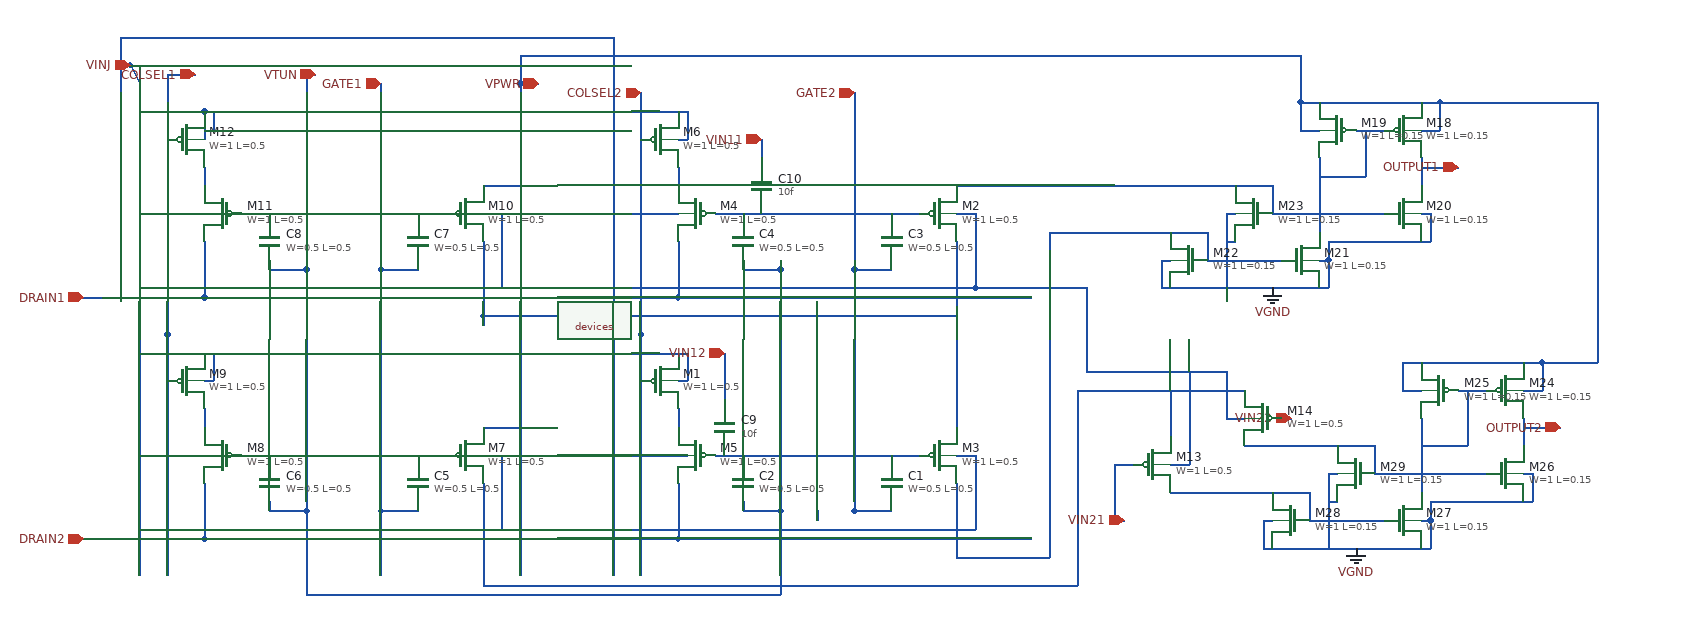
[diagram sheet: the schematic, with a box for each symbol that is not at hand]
v {xschem version=2.9.9 file_version=1.2 }
G {}
K {}
V {}
S {}
E {}
N 1300 -1430 1330 -1430 { lab=#net1}
N 1260 -1380 1260 -1370 { lab=GATE2}
N 1260 -1370 1300 -1370 { lab=GATE2}
N 1140 -1430 1300 -1430 { lab=#net1}
N 1140 -1370 1180 -1370 { lab=VTUN}
N 1140 -1380 1140 -1370 { lab=VTUN}
N 1110 -1430 1140 -1430 { lab=#net1}
N 1070 -1480 1070 -1460 { lab=#net2}
N 1370 -1400 1370 -1320 { lab=#net3}
N 1180 -1380 1180 -1370 { lab=VTUN}
N 1180 -1370 1180 -1300 { lab=VTUN}
N 1180 -1560 1180 -1370 { lab=VTUN}
N 1030 -1560 1030 -1510 { lab=COLSEL2}
N 1030 -1560 1030 -1300 { lab=COLSEL2}
N 1070 -1400 1070 -1340 { lab=DRAIN2}
N 950 -1340 1070 -1340 { lab=DRAIN2}
N 1070 -1340 1220 -1340 { lab=DRAIN2}
N 1220 -1340 1320 -1340 { lab=DRAIN2}
N 1320 -1340 1390 -1340 { lab=DRAIN2}
N 1390 -1340 1450 -1340 { lab=DRAIN2}
N 1000 -1560 1000 -1300 { lab=VINJ}
N 1000 -1540 1070 -1540 { lab=VINJ}
N 1300 -1690 1330 -1690 { lab=#net4}
N 1260 -1640 1260 -1630 { lab=GATE2}
N 1260 -1630 1300 -1630 { lab=GATE2}
N 1140 -1690 1300 -1690 { lab=#net4}
N 1140 -1630 1180 -1630 { lab=VTUN}
N 1140 -1640 1140 -1630 { lab=VTUN}
N 1110 -1690 1140 -1690 { lab=#net4}
N 1070 -1740 1070 -1720 { lab=#net5}
N 1370 -1660 1370 -1580 { lab=#net6}
N 1370 -1720 1410 -1720 { lab=#net7}
N 1260 -1630 1260 -1560 { lab=GATE2}
N 1180 -1640 1180 -1630 { lab=VTUN}
N 1180 -1630 1180 -1560 { lab=VTUN}
N 1030 -1820 1030 -1770 { lab=COLSEL2}
N 1030 -1820 1030 -1560 { lab=COLSEL2}
N 1070 -1660 1070 -1600 { lab=DRAIN1}
N 950 -1600 1070 -1600 { lab=DRAIN1}
N 1070 -1600 1220 -1600 { lab=DRAIN1}
N 1220 -1600 1320 -1600 { lab=DRAIN1}
N 1320 -1600 1390 -1600 { lab=DRAIN1}
N 1390 -1600 1450 -1600 { lab=DRAIN1}
N 1000 -1820 1000 -1560 { lab=VINJ}
N 1000 -1800 1070 -1800 { lab=VINJ}
N 790 -1430 820 -1430 { lab=#net8}
N 750 -1380 750 -1370 { lab=GATE1}
N 750 -1370 790 -1370 { lab=GATE1}
N 630 -1430 790 -1430 { lab=#net8}
N 630 -1370 670 -1370 { lab=VTUN}
N 630 -1380 630 -1370 { lab=VTUN}
N 600 -1430 630 -1430 { lab=#net8}
N 560 -1480 560 -1460 { lab=#net9}
N 900 -1560 900 -1350 { lab=VPWR}
N 900 -1350 900 -1300 { lab=VPWR}
N 860 -1400 860 -1320 { lab=#net10}
N 860 -1460 900 -1460 { lab=VPWR}
N 750 -1370 750 -1300 { lab=GATE1}
N 750 -1560 750 -1370 { lab=GATE1}
N 670 -1380 670 -1370 { lab=VTUN}
N 670 -1370 670 -1300 { lab=VTUN}
N 670 -1560 670 -1370 { lab=VTUN}
N 520 -1560 520 -1510 { lab=COLSEL1}
N 520 -1560 520 -1300 { lab=COLSEL1}
N 560 -1400 560 -1340 { lab=DRAIN2}
N 440 -1340 560 -1340 { lab=DRAIN2}
N 560 -1340 710 -1340 { lab=DRAIN2}
N 710 -1340 810 -1340 { lab=DRAIN2}
N 810 -1340 880 -1340 { lab=DRAIN2}
N 880 -1340 940 -1340 { lab=DRAIN2}
N 490 -1560 490 -1300 { lab=VINJ}
N 490 -1540 560 -1540 { lab=VINJ}
N 790 -1690 820 -1690 { lab=#net11}
N 750 -1640 750 -1630 { lab=GATE1}
N 750 -1630 790 -1630 { lab=GATE1}
N 630 -1690 790 -1690 { lab=#net11}
N 630 -1630 670 -1630 { lab=VTUN}
N 630 -1640 630 -1630 { lab=VTUN}
N 600 -1690 630 -1690 { lab=#net11}
N 560 -1740 560 -1720 { lab=#net12}
N 900 -1820 900 -1610 { lab=VPWR}
N 900 -1610 900 -1560 { lab=VPWR}
N 860 -1660 860 -1580 { lab=#net6}
N 860 -1720 900 -1720 { lab=VPWR}
N 750 -1630 750 -1560 { lab=GATE1}
N 750 -1820 750 -1630 { lab=GATE1}
N 670 -1640 670 -1630 { lab=VTUN}
N 670 -1630 670 -1560 { lab=VTUN}
N 670 -1820 670 -1630 { lab=VTUN}
N 520 -1820 520 -1770 { lab=COLSEL1}
N 520 -1820 520 -1560 { lab=COLSEL1}
N 560 -1660 560 -1600 { lab=DRAIN1}
N 440 -1600 560 -1600 { lab=DRAIN1}
N 560 -1600 710 -1600 { lab=DRAIN1}
N 710 -1600 810 -1600 { lab=DRAIN1}
N 810 -1600 880 -1600 { lab=DRAIN1}
N 880 -1600 940 -1600 { lab=DRAIN1}
N 490 -1820 490 -1560 { lab=VINJ}
N 490 -1800 560 -1800 { lab=VINJ}
N 420 -1600 440 -1600 { lab=DRAIN1}
N 420 -1340 450 -1340 { lab=DRAIN2}
N 420 -1600 450 -1600 { lab=DRAIN1}
N 930 -1600 960 -1600 { lab=DRAIN1}
N 930 -1340 960 -1340 { lab=DRAIN2}
N 900 -1830 900 -1810 { lab=VPWR}
N 750 -1830 750 -1810 { lab=GATE1}
N 670 -1830 670 -1810 { lab=VTUN}
N 520 -1830 520 -1810 { lab=COLSEL1}
N 490 -1850 490 -1820 { lab=VINJ}
N 480 -1850 490 -1830 { lab=VINJ}
N 480 -1850 490 -1830 { lab=VINJ}
N 560 -1800 560 -1770 { lab=VINJ}
N 560 -1780 570 -1780 { lab=VINJ}
N 570 -1800 570 -1780 { lab=VINJ}
N 560 -1800 570 -1800 { lab=VINJ}
N 490 -1690 560 -1690 { lab=VINJ}
N 490 -1430 560 -1430 { lab=VINJ}
N 560 -1510 570 -1510 { lab=VINJ}
N 570 -1540 570 -1510 { lab=VINJ}
N 540 -1540 570 -1540 { lab=VINJ}
N 1000 -1690 1070 -1690 { lab=VINJ}
N 1070 -1770 1080 -1770 { lab=VINJ}
N 1080 -1800 1080 -1770 { lab=VINJ}
N 1050 -1800 1080 -1800 { lab=VINJ}
N 1000 -1430 1080 -1430 { lab=VINJ}
N 1070 -1510 1080 -1510 { lab=VINJ}
N 1080 -1540 1080 -1510 { lab=VINJ}
N 1050 -1540 1080 -1540 { lab=VINJ}
N 1000 -1350 1390 -1350 { lab=VINJ}
N 1390 -1430 1390 -1350 { lab=VINJ}
N 1370 -1430 1390 -1430 { lab=VINJ}
N 1370 -1690 1390 -1690 { lab=VINJ}
N 1390 -1690 1390 -1610 { lab=VINJ}
N 1000 -1610 1390 -1610 { lab=VINJ}
N 860 -1430 880 -1430 { lab=VINJ}
N 880 -1430 880 -1350 { lab=VINJ}
N 490 -1350 880 -1350 { lab=VINJ}
N 860 -1690 880 -1690 { lab=VINJ}
N 880 -1690 880 -1610 { lab=VINJ}
N 490 -1610 880 -1610 { lab=VINJ}
N 520 -1840 520 -1830 { lab=COLSEL1}
N 520 -1840 550 -1840 { lab=COLSEL1}
N 900 -1830 920 -1830 { lab=VPWR}
N 670 -1840 670 -1830 { lab=VTUN}
N 670 -1840 680 -1840 { lab=VTUN}
N 1000 -1880 1000 -1820 { lab=VINJ}
N 470 -1880 1000 -1880 { lab=VINJ}
N 470 -1880 470 -1820 { lab=VINJ}
N 470 -1850 480 -1850 { lab=VINJ}
N 1800 -1780 1830 -1780 { lab=#net13}
N 1870 -1780 1890 -1780 { lab=VPWR}
N 1890 -1810 1890 -1780 { lab=VPWR}
N 1870 -1810 1890 -1810 { lab=VPWR}
N 1760 -1810 1870 -1810 { lab=VPWR}
N 1740 -1810 1760 -1810 { lab=VPWR}
N 1740 -1810 1740 -1780 { lab=VPWR}
N 1740 -1780 1760 -1780 { lab=VPWR}
N 1870 -1750 1870 -1720 { lab=OUTPUT1}
N 1870 -1740 1910 -1740 { lab=OUTPUT1}
N 1760 -1750 1760 -1670 { lab=#net13}
N 1710 -1690 1830 -1690 { lab=#net7}
N 1710 -1720 1710 -1690 { lab=#net7}
N 1670 -1720 1710 -1720 { lab=#net7}
N 1530 -1720 1670 -1720 { lab=#net7}
N 1640 -1640 1720 -1640 { lab=#net3}
N 1640 -1670 1640 -1640 { lab=#net3}
N 1600 -1670 1640 -1670 { lab=#net3}
N 1530 -1670 1600 -1670 { lab=#net3}
N 1590 -1640 1600 -1640 { lab=VGND}
N 1590 -1640 1590 -1610 { lab=VGND}
N 1590 -1610 1600 -1610 { lab=VGND}
N 1600 -1610 1760 -1610 { lab=VGND}
N 1760 -1610 1770 -1610 { lab=VGND}
N 1770 -1640 1770 -1610 { lab=VGND}
N 1760 -1640 1770 -1640 { lab=VGND}
N 1870 -1690 1880 -1690 { lab=VGND}
N 1880 -1690 1880 -1660 { lab=VGND}
N 1870 -1660 1880 -1660 { lab=VGND}
N 1800 -1660 1870 -1660 { lab=VGND}
N 1770 -1660 1800 -1660 { lab=VGND}
N 1770 -1660 1770 -1640 { lab=VGND}
N 1660 -1690 1670 -1690 { lab=VGND}
N 1660 -1690 1660 -1610 { lab=VGND}
N 1660 -1660 1670 -1660 { lab=VGND}
N 1910 -1500 1940 -1500 { lab=#net14}
N 1980 -1500 2000 -1500 { lab=VPWR}
N 2000 -1530 2000 -1500 { lab=VPWR}
N 1980 -1530 2000 -1530 { lab=VPWR}
N 1870 -1530 1980 -1530 { lab=VPWR}
N 1850 -1530 1870 -1530 { lab=VPWR}
N 1850 -1530 1850 -1500 { lab=VPWR}
N 1850 -1500 1870 -1500 { lab=VPWR}
N 1980 -1470 1980 -1440 { lab=OUTPUT2}
N 1980 -1460 2020 -1460 { lab=OUTPUT2}
N 1870 -1470 1870 -1390 { lab=#net14}
N 1820 -1410 1940 -1410 { lab=#net15}
N 1820 -1440 1820 -1410 { lab=#net15}
N 1780 -1440 1820 -1440 { lab=#net15}
N 1750 -1360 1830 -1360 { lab=#net16}
N 1750 -1390 1750 -1360 { lab=#net16}
N 1710 -1390 1750 -1390 { lab=#net16}
N 1640 -1390 1710 -1390 { lab=#net16}
N 1700 -1360 1710 -1360 { lab=VGND}
N 1700 -1360 1700 -1330 { lab=VGND}
N 1700 -1330 1710 -1330 { lab=VGND}
N 1710 -1330 1870 -1330 { lab=VGND}
N 1870 -1330 1880 -1330 { lab=VGND}
N 1880 -1360 1880 -1330 { lab=VGND}
N 1870 -1360 1880 -1360 { lab=VGND}
N 1980 -1410 1990 -1410 { lab=VGND}
N 1990 -1410 1990 -1380 { lab=VGND}
N 1980 -1380 1990 -1380 { lab=VGND}
N 1910 -1380 1980 -1380 { lab=VGND}
N 1880 -1380 1910 -1380 { lab=VGND}
N 1880 -1380 1880 -1360 { lab=VGND}
N 1770 -1410 1780 -1410 { lab=VGND}
N 1770 -1410 1770 -1330 { lab=VGND}
N 1770 -1380 1780 -1380 { lab=VGND}
N 670 -1300 670 -1280 { lab=VTUN}
N 670 -1280 1180 -1280 { lab=VTUN}
N 1180 -1310 1180 -1280 { lab=VTUN}
N 860 -1580 860 -1570 { lab=#net6}
N 860 -1320 860 -1290 { lab=#net10}
N 860 -1290 1500 -1290 { lab=#net10}
N 1370 -1590 1370 -1460 { lab=#net6}
N 1400 -1720 1490 -1720 { lab=#net7}
N 1220 -1370 1220 -1360 { lab=#net17}
N 860 -1580 1370 -1580 { lab=#net6}
N 1470 -1650 1470 -1320 { lab=#net3}
N 1370 -1320 1470 -1320 { lab=#net3}
N 900 -1860 900 -1830 { lab=VPWR}
N 900 -1860 1740 -1860 { lab=VPWR}
N 1740 -1860 1740 -1810 { lab=VPWR}
N 1480 -1720 1540 -1720 { lab=#net7}
N 1470 -1670 1530 -1670 { lab=#net3}
N 1470 -1670 1470 -1640 { lab=#net3}
N 1680 -1440 1780 -1440 { lab=#net15}
N 1600 -1390 1640 -1390 { lab=#net16}
N 1720 -1470 1730 -1470 { lab=VIN22}
N 1540 -1420 1560 -1420 { lab=VIN21}
N 1540 -1420 1540 -1360 { lab=VIN21}
N 1540 -1360 1550 -1360 { lab=VIN21}
N 1500 -1500 1500 -1290 { lab=#net10}
N 1500 -1500 1680 -1500 { lab=#net10}
N 1600 -1500 1600 -1450 { lab=#net10}
N 1390 -1610 1460 -1610 { lab=VINJ}
N 1460 -1610 1510 -1610 { lab=VINJ}
N 1510 -1610 1510 -1520 { lab=VINJ}
N 1510 -1520 1660 -1520 { lab=VINJ}
N 1660 -1520 1660 -1470 { lab=VINJ}
N 1660 -1470 1680 -1470 { lab=VINJ}
N 1600 -1420 1620 -1420 { lab=VINJ}
N 1620 -1490 1620 -1420 { lab=VINJ}
N 1620 -1510 1620 -1490 { lab=VINJ}
N 1620 -1520 1620 -1510 { lab=VINJ}
N 2000 -1530 2060 -1530 { lab=VPWR}
N 2060 -1810 2060 -1530 { lab=VPWR}
N 1890 -1810 2060 -1810 { lab=VPWR}
N 1760 -1730 1810 -1730 { lab=#net13}
N 1810 -1780 1810 -1730 { lab=#net13}
N 1870 -1440 1920 -1440 { lab=#net14}
N 1920 -1500 1920 -1440 { lab=#net14}
N 1260 -1820 1260 -1630 { lab=GATE2}
N 1260 -1560 1260 -1370 { lab=GATE2}
N 1160 -1770 1160 -1750 { lab=VIN11}
N 1120 -1540 1120 -1490 { lab=VIN12}
C {sky130_fd_pr/pfet_g5v0d10v5.sym} 1350 -1430 0 0 {name=M3
L=0.5
W=1
nf=1
mult=1
ad="'int((nf+1)/2) * W/nf * 0.29'" 
pd="'2*int((nf+1)/2) * (W/nf + 0.29)'"
as="'int((nf+2)/2) * W/nf * 0.29'" 
ps="'2*int((nf+2)/2) * (W/nf + 0.29)'"
nrd="'0.29 / W'" nrs="'0.29 / W'"
sa=0 sb=0 sd=0
model=pfet_g5v0d10v5
spiceprefix=X
}
C {sky130_fd_pr/cap_var_hvt.sym} 1300 -1400 0 0 {name=C1 model=cap_var_hvt W=0.5 L=0.5 VM=1 spiceprefix=X}
C {sky130_fd_pr/pfet_g5v0d10v5.sym} 1090 -1430 0 1 {name=M5
L=0.5
W=1
nf=1
mult=1
ad="'int((nf+1)/2) * W/nf * 0.29'" 
pd="'2*int((nf+1)/2) * (W/nf + 0.29)'"
as="'int((nf+2)/2) * W/nf * 0.29'" 
ps="'2*int((nf+2)/2) * (W/nf + 0.29)'"
nrd="'0.29 / W'" nrs="'0.29 / W'"
sa=0 sb=0 sd=0
model=pfet_g5v0d10v5
spiceprefix=X
}
C {sky130_fd_pr/cap_var_hvt.sym} 1140 -1400 0 1 {name=C2 model=cap_var_hvt W=0.5 L=0.5 VM=1 spiceprefix=X}
C {sky130_fd_pr/pfet_g5v0d10v5.sym} 1050 -1510 0 0 {name=M1
L=0.5
W=1
nf=1
mult=1
ad="'int((nf+1)/2) * W/nf * 0.29'" 
pd="'2*int((nf+1)/2) * (W/nf + 0.29)'"
as="'int((nf+2)/2) * W/nf * 0.29'" 
ps="'2*int((nf+2)/2) * (W/nf + 0.29)'"
nrd="'0.29 / W'" nrs="'0.29 / W'"
sa=0 sb=0 sd=0
model=pfet_g5v0d10v5
spiceprefix=X
}
C {sky130_fd_pr/pfet_g5v0d10v5.sym} 1350 -1690 0 0 {name=M2
L=0.5
W=1
nf=1
mult=1
ad="'int((nf+1)/2) * W/nf * 0.29'" 
pd="'2*int((nf+1)/2) * (W/nf + 0.29)'"
as="'int((nf+2)/2) * W/nf * 0.29'" 
ps="'2*int((nf+2)/2) * (W/nf + 0.29)'"
nrd="'0.29 / W'" nrs="'0.29 / W'"
sa=0 sb=0 sd=0
model=pfet_g5v0d10v5
spiceprefix=X
}
C {sky130_fd_pr/cap_var_hvt.sym} 1300 -1660 0 0 {name=C3 model=cap_var_hvt W=0.5 L=0.5 VM=1 spiceprefix=X}
C {sky130_fd_pr/pfet_g5v0d10v5.sym} 1090 -1690 0 1 {name=M4
L=0.5
W=1
nf=1
mult=1
ad="'int((nf+1)/2) * W/nf * 0.29'" 
pd="'2*int((nf+1)/2) * (W/nf + 0.29)'"
as="'int((nf+2)/2) * W/nf * 0.29'" 
ps="'2*int((nf+2)/2) * (W/nf + 0.29)'"
nrd="'0.29 / W'" nrs="'0.29 / W'"
sa=0 sb=0 sd=0
model=pfet_g5v0d10v5
spiceprefix=X
}
C {sky130_fd_pr/cap_var_hvt.sym} 1140 -1660 0 1 {name=C4 model=cap_var_hvt W=0.5 L=0.5 VM=1 spiceprefix=X}
C {sky130_fd_pr/pfet_g5v0d10v5.sym} 1050 -1770 0 0 {name=M6
L=0.5
W=1
nf=1
mult=1
ad="'int((nf+1)/2) * W/nf * 0.29'" 
pd="'2*int((nf+1)/2) * (W/nf + 0.29)'"
as="'int((nf+2)/2) * W/nf * 0.29'" 
ps="'2*int((nf+2)/2) * (W/nf + 0.29)'"
nrd="'0.29 / W'" nrs="'0.29 / W'"
sa=0 sb=0 sd=0
model=pfet_g5v0d10v5
spiceprefix=X
}
C {sky130_fd_pr/pfet_g5v0d10v5.sym} 840 -1430 0 0 {name=M7
L=0.5
W=1
nf=1
mult=1
ad="'int((nf+1)/2) * W/nf * 0.29'" 
pd="'2*int((nf+1)/2) * (W/nf + 0.29)'"
as="'int((nf+2)/2) * W/nf * 0.29'" 
ps="'2*int((nf+2)/2) * (W/nf + 0.29)'"
nrd="'0.29 / W'" nrs="'0.29 / W'"
sa=0 sb=0 sd=0
model=pfet_g5v0d10v5
spiceprefix=X
}
C {sky130_fd_pr/cap_var_hvt.sym} 790 -1400 0 0 {name=C5 model=cap_var_hvt W=0.5 L=0.5 VM=1 spiceprefix=X}
C {sky130_fd_pr/pfet_g5v0d10v5.sym} 580 -1430 0 1 {name=M8
L=0.5
W=1
nf=1
mult=1
ad="'int((nf+1)/2) * W/nf * 0.29'" 
pd="'2*int((nf+1)/2) * (W/nf + 0.29)'"
as="'int((nf+2)/2) * W/nf * 0.29'" 
ps="'2*int((nf+2)/2) * (W/nf + 0.29)'"
nrd="'0.29 / W'" nrs="'0.29 / W'"
sa=0 sb=0 sd=0
model=pfet_g5v0d10v5
spiceprefix=X
}
C {sky130_fd_pr/cap_var_hvt.sym} 630 -1400 0 1 {name=C6 model=cap_var_hvt W=0.5 L=0.5 VM=1 spiceprefix=X}
C {sky130_fd_pr/pfet_g5v0d10v5.sym} 540 -1510 0 0 {name=M9
L=0.5
W=1
nf=1
mult=1
ad="'int((nf+1)/2) * W/nf * 0.29'" 
pd="'2*int((nf+1)/2) * (W/nf + 0.29)'"
as="'int((nf+2)/2) * W/nf * 0.29'" 
ps="'2*int((nf+2)/2) * (W/nf + 0.29)'"
nrd="'0.29 / W'" nrs="'0.29 / W'"
sa=0 sb=0 sd=0
model=pfet_g5v0d10v5
spiceprefix=X
}
C {sky130_fd_pr/pfet_g5v0d10v5.sym} 840 -1690 0 0 {name=M10
L=0.5
W=1
nf=1
mult=1
ad="'int((nf+1)/2) * W/nf * 0.29'" 
pd="'2*int((nf+1)/2) * (W/nf + 0.29)'"
as="'int((nf+2)/2) * W/nf * 0.29'" 
ps="'2*int((nf+2)/2) * (W/nf + 0.29)'"
nrd="'0.29 / W'" nrs="'0.29 / W'"
sa=0 sb=0 sd=0
model=pfet_g5v0d10v5
spiceprefix=X
}
C {sky130_fd_pr/cap_var_hvt.sym} 790 -1660 0 0 {name=C7 model=cap_var_hvt W=0.5 L=0.5 VM=1 spiceprefix=X}
C {sky130_fd_pr/pfet_g5v0d10v5.sym} 580 -1690 0 1 {name=M11
L=0.5
W=1
nf=1
mult=1
ad="'int((nf+1)/2) * W/nf * 0.29'" 
pd="'2*int((nf+1)/2) * (W/nf + 0.29)'"
as="'int((nf+2)/2) * W/nf * 0.29'" 
ps="'2*int((nf+2)/2) * (W/nf + 0.29)'"
nrd="'0.29 / W'" nrs="'0.29 / W'"
sa=0 sb=0 sd=0
model=pfet_g5v0d10v5
spiceprefix=X
}
C {sky130_fd_pr/cap_var_hvt.sym} 630 -1660 0 1 {name=C8 model=cap_var_hvt W=0.5 L=0.5 VM=1 spiceprefix=X}
C {sky130_fd_pr/pfet_g5v0d10v5.sym} 540 -1770 0 0 {name=M12
L=0.5
W=1
nf=1
mult=1
ad="'int((nf+1)/2) * W/nf * 0.29'" 
pd="'2*int((nf+1)/2) * (W/nf + 0.29)'"
as="'int((nf+2)/2) * W/nf * 0.29'" 
ps="'2*int((nf+2)/2) * (W/nf + 0.29)'"
nrd="'0.29 / W'" nrs="'0.29 / W'"
sa=0 sb=0 sd=0
model=pfet_g5v0d10v5
spiceprefix=X
}
C {devices} 980 -1480 0 0 {}
C {devices/ipin.sym} 430 -1600 0 0 {name=Drain1 lab=DRAIN1}
C {devices/ipin.sym} 430 -1340 0 0 {name=Drain2 lab=DRAIN2}
C {devices/iopin.sym} 920 -1830 0 0 {name=Vdd lab=VPWR}
C {devices/iopin.sym} 750 -1830 0 0 {name=Gate1 lab=GATE1}
C {devices/iopin.sym} 680 -1840 0 0 {name=Vtun lab=VTUN}
C {devices/iopin.sym} 550 -1840 0 0 {name=ColSel1 lab=COLSEL1}
C {devices/iopin.sym} 480 -1850 0 0 {name=Vinj lab=VINJ}
C {devices/iopin.sym} 1030 -1820 0 0 {name=ColSel2 lab=COLSEL2}
C {devices/iopin.sym} 1260 -1820 0 0 {name=Gate2 lab=GATE2}
C {sky130_fd_pr/pfet_01v8.sym} 1850 -1780 0 0 {name=M18
L=0.15
W=1
nf=1
mult=1
ad="'int((nf+1)/2) * W/nf * 0.29'" 
pd="'2*int((nf+1)/2) * (W/nf + 0.29)'"
as="'int((nf+2)/2) * W/nf * 0.29'" 
ps="'2*int((nf+2)/2) * (W/nf + 0.29)'"
nrd="'0.29 / W'" nrs="'0.29 / W'"
sa=0 sb=0 sd=0
model=pfet_01v8
spiceprefix=X
}
C {sky130_fd_pr/pfet_01v8.sym} 1780 -1780 0 1 {name=M19
L=0.15
W=1
nf=1
mult=1
ad="'int((nf+1)/2) * W/nf * 0.29'" 
pd="'2*int((nf+1)/2) * (W/nf + 0.29)'"
as="'int((nf+2)/2) * W/nf * 0.29'" 
ps="'2*int((nf+2)/2) * (W/nf + 0.29)'"
nrd="'0.29 / W'" nrs="'0.29 / W'"
sa=0 sb=0 sd=0
model=pfet_01v8
spiceprefix=X
}
C {sky130_fd_pr/nfet_01v8.sym} 1850 -1690 0 0 {name=M20
L=0.15
W=1
nf=1 
mult=1
ad="'int((nf+1)/2) * W/nf * 0.29'" 
pd="'2*int((nf+1)/2) * (W/nf + 0.29)'"
as="'int((nf+2)/2) * W/nf * 0.29'" 
ps="'2*int((nf+2)/2) * (W/nf + 0.29)'"
nrd="'0.29 / W'" nrs="'0.29 / W'"
sa=0 sb=0 sd=0
model=nfet_01v8
spiceprefix=X
}
C {sky130_fd_pr/nfet_01v8.sym} 1740 -1640 0 0 {name=M21
L=0.15
W=1
nf=1 
mult=1
ad="'int((nf+1)/2) * W/nf * 0.29'" 
pd="'2*int((nf+1)/2) * (W/nf + 0.29)'"
as="'int((nf+2)/2) * W/nf * 0.29'" 
ps="'2*int((nf+2)/2) * (W/nf + 0.29)'"
nrd="'0.29 / W'" nrs="'0.29 / W'"
sa=0 sb=0 sd=0
model=nfet_01v8
spiceprefix=X
}
C {sky130_fd_pr/nfet_01v8.sym} 1620 -1640 0 1 {name=M22
L=0.15
W=1
nf=1 
mult=1
ad="'int((nf+1)/2) * W/nf * 0.29'" 
pd="'2*int((nf+1)/2) * (W/nf + 0.29)'"
as="'int((nf+2)/2) * W/nf * 0.29'" 
ps="'2*int((nf+2)/2) * (W/nf + 0.29)'"
nrd="'0.29 / W'" nrs="'0.29 / W'"
sa=0 sb=0 sd=0
model=nfet_01v8
spiceprefix=X
}
C {sky130_fd_pr/nfet_01v8.sym} 1690 -1690 0 1 {name=M23
L=0.15
W=1
nf=1 
mult=1
ad="'int((nf+1)/2) * W/nf * 0.29'" 
pd="'2*int((nf+1)/2) * (W/nf + 0.29)'"
as="'int((nf+2)/2) * W/nf * 0.29'" 
ps="'2*int((nf+2)/2) * (W/nf + 0.29)'"
nrd="'0.29 / W'" nrs="'0.29 / W'"
sa=0 sb=0 sd=0
model=nfet_01v8
spiceprefix=X
}
C {devices/iopin.sym} 1910 -1740 0 0 {name=Output1 lab=OUTPUT1}
C {sky130_fd_pr/pfet_01v8.sym} 1960 -1500 0 0 {name=M24
L=0.15
W=1
nf=1
mult=1
ad="'int((nf+1)/2) * W/nf * 0.29'" 
pd="'2*int((nf+1)/2) * (W/nf + 0.29)'"
as="'int((nf+2)/2) * W/nf * 0.29'" 
ps="'2*int((nf+2)/2) * (W/nf + 0.29)'"
nrd="'0.29 / W'" nrs="'0.29 / W'"
sa=0 sb=0 sd=0
model=pfet_01v8
spiceprefix=X
}
C {sky130_fd_pr/pfet_01v8.sym} 1890 -1500 0 1 {name=M25
L=0.15
W=1
nf=1
mult=1
ad="'int((nf+1)/2) * W/nf * 0.29'" 
pd="'2*int((nf+1)/2) * (W/nf + 0.29)'"
as="'int((nf+2)/2) * W/nf * 0.29'" 
ps="'2*int((nf+2)/2) * (W/nf + 0.29)'"
nrd="'0.29 / W'" nrs="'0.29 / W'"
sa=0 sb=0 sd=0
model=pfet_01v8
spiceprefix=X
}
C {sky130_fd_pr/nfet_01v8.sym} 1960 -1410 0 0 {name=M26
L=0.15
W=1
nf=1 
mult=1
ad="'int((nf+1)/2) * W/nf * 0.29'" 
pd="'2*int((nf+1)/2) * (W/nf + 0.29)'"
as="'int((nf+2)/2) * W/nf * 0.29'" 
ps="'2*int((nf+2)/2) * (W/nf + 0.29)'"
nrd="'0.29 / W'" nrs="'0.29 / W'"
sa=0 sb=0 sd=0
model=nfet_01v8
spiceprefix=X
}
C {sky130_fd_pr/nfet_01v8.sym} 1850 -1360 0 0 {name=M27
L=0.15
W=1
nf=1 
mult=1
ad="'int((nf+1)/2) * W/nf * 0.29'" 
pd="'2*int((nf+1)/2) * (W/nf + 0.29)'"
as="'int((nf+2)/2) * W/nf * 0.29'" 
ps="'2*int((nf+2)/2) * (W/nf + 0.29)'"
nrd="'0.29 / W'" nrs="'0.29 / W'"
sa=0 sb=0 sd=0
model=nfet_01v8
spiceprefix=X
}
C {sky130_fd_pr/nfet_01v8.sym} 1730 -1360 0 1 {name=M28
L=0.15
W=1
nf=1 
mult=1
ad="'int((nf+1)/2) * W/nf * 0.29'" 
pd="'2*int((nf+1)/2) * (W/nf + 0.29)'"
as="'int((nf+2)/2) * W/nf * 0.29'" 
ps="'2*int((nf+2)/2) * (W/nf + 0.29)'"
nrd="'0.29 / W'" nrs="'0.29 / W'"
sa=0 sb=0 sd=0
model=nfet_01v8
spiceprefix=X
}
C {sky130_fd_pr/nfet_01v8.sym} 1800 -1410 0 1 {name=M29
L=0.15
W=1
nf=1 
mult=1
ad="'int((nf+1)/2) * W/nf * 0.29'" 
pd="'2*int((nf+1)/2) * (W/nf + 0.29)'"
as="'int((nf+2)/2) * W/nf * 0.29'" 
ps="'2*int((nf+2)/2) * (W/nf + 0.29)'"
nrd="'0.29 / W'" nrs="'0.29 / W'"
sa=0 sb=0 sd=0
model=nfet_01v8
spiceprefix=X
}
C {devices/iopin.sym} 2020 -1460 0 0 {name=Output2 lab=OUTPUT2}
C {devices/iopin.sym} 1160 -1770 0 0 {name=Vin11 lab=VIN11}
C {devices/iopin.sym} 1550 -1360 0 0 {name=Vin21 lab=VIN21}
C {devices/iopin.sym} 1120 -1540 0 0 {name=Vin12 lab=VIN12}
C {devices/iopin.sym} 1730 -1470 0 0 {name=Vin22 lab=VIN22}
C {sky130_fd_pr/pfet_g5v0d10v5.sym} 1580 -1420 0 0 {name=M13
L=0.5
W=1
nf=1
mult=1
ad="'int((nf+1)/2) * W/nf * 0.29'" 
pd="'2*int((nf+1)/2) * (W/nf + 0.29)'"
as="'int((nf+2)/2) * W/nf * 0.29'" 
ps="'2*int((nf+2)/2) * (W/nf + 0.29)'"
nrd="'0.29 / W'" nrs="'0.29 / W'"
sa=0 sb=0 sd=0
model=pfet_g5v0d10v5
spiceprefix=X
}
C {sky130_fd_pr/pfet_g5v0d10v5.sym} 1700 -1470 0 1 {name=M14
L=0.5
W=1
nf=1
mult=1
ad="'int((nf+1)/2) * W/nf * 0.29'" 
pd="'2*int((nf+1)/2) * (W/nf + 0.29)'"
as="'int((nf+2)/2) * W/nf * 0.29'" 
ps="'2*int((nf+2)/2) * (W/nf + 0.29)'"
nrd="'0.29 / W'" nrs="'0.29 / W'"
sa=0 sb=0 sd=0
model=pfet_g5v0d10v5
spiceprefix=X
}
C {devices/gnd.sym} 1800 -1330 0 0 {name=l1 lab=VGND}
C {devices/gnd.sym} 1710 -1610 0 0 {name=l2 lab=VGND}
C {devices/capa.sym} 1120 -1460 0 0 {name=C9
value=10f
}
C {devices/capa.sym} 1160 -1720 0 0 {name=C10
value=10f
}
